One B-rep face of a CAD part: STEP entity #14088.
In plain terms, the planar face has unit normal (0, 0, -1).
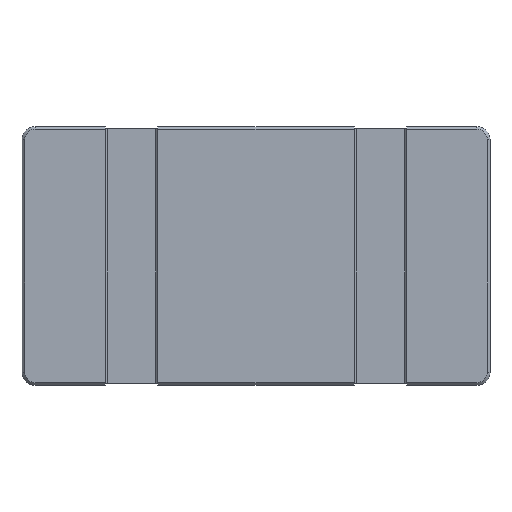
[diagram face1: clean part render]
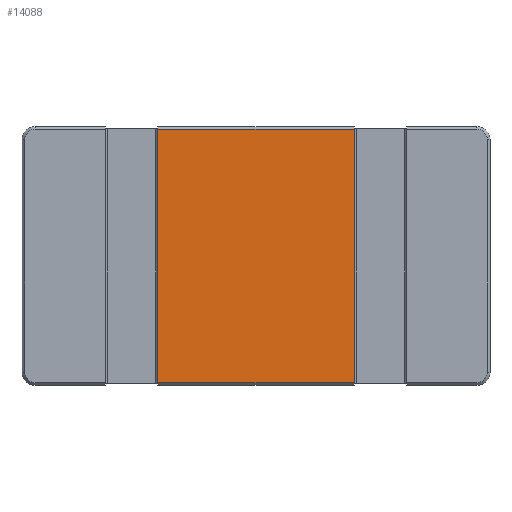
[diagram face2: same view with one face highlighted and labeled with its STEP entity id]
Its self-contained STEP definition (entity closure, numbers rounded to 3 decimals):
#10354 = PLANE('',#10355);
#10355 = AXIS2_PLACEMENT_3D('',#10356,#10357,#10358);
#10356 = CARTESIAN_POINT('',(-67.5,39.1,0.4));
#10357 = DIRECTION('',(0.,-0.707,0.707
    ));
#10358 = DIRECTION('',(-1.,0.,0.));
#11414 = PLANE('',#11415);
#11415 = AXIS2_PLACEMENT_3D('',#11416,#11417,#11418);
#11416 = CARTESIAN_POINT('',(67.5,-39.1,0.4));
#11417 = DIRECTION('',(0.,-0.707,
    -0.707));
#11418 = DIRECTION('',(-1.,0.,0.));
#12497 = PLANE('',#12498);
#12498 = AXIS2_PLACEMENT_3D('',#12499,#12500,#12501);
#12499 = CARTESIAN_POINT('',(-30.,-40.5,0.));
#12500 = DIRECTION('',(1.,0.,-0.));
#12501 = DIRECTION('',(0.,0.,1.));
#12560 = VERTEX_POINT('',#12561);
#12561 = CARTESIAN_POINT('',(30.,38.7,0.));
#12574 = PLANE('',#12575);
#12575 = AXIS2_PLACEMENT_3D('',#12576,#12577,#12578);
#12576 = CARTESIAN_POINT('',(30.,-40.5,0.));
#12577 = DIRECTION('',(1.,0.,-0.));
#12578 = DIRECTION('',(0.,0.,1.));
#12585 = EDGE_CURVE('',#12586,#12560,#12588,.T.);
#12586 = VERTEX_POINT('',#12587);
#12587 = CARTESIAN_POINT('',(-30.,38.7,0.));
#12588 = SURFACE_CURVE('',#12589,(#12593,#12600),.PCURVE_S1.);
#12589 = LINE('',#12590,#12591);
#12590 = CARTESIAN_POINT('',(-67.5,38.7,0.));
#12591 = VECTOR('',#12592,1.);
#12592 = DIRECTION('',(1.,0.,-0.));
#12593 = PCURVE('',#10354,#12594);
#12594 = DEFINITIONAL_REPRESENTATION('',(#12595),#12599);
#12595 = LINE('',#12596,#12597);
#12596 = CARTESIAN_POINT('',(-0.,0.566));
#12597 = VECTOR('',#12598,1.);
#12598 = DIRECTION('',(-1.,0.));
#12599 = ( GEOMETRIC_REPRESENTATION_CONTEXT(2) 
PARAMETRIC_REPRESENTATION_CONTEXT() REPRESENTATION_CONTEXT('2D SPACE',''
  ) );
#12600 = PCURVE('',#12601,#12606);
#12601 = PLANE('',#12602);
#12602 = AXIS2_PLACEMENT_3D('',#12603,#12604,#12605);
#12603 = CARTESIAN_POINT('',(-71.5,-39.5,0.));
#12604 = DIRECTION('',(0.,0.,1.));
#12605 = DIRECTION('',(1.,0.,-0.));
#12606 = DEFINITIONAL_REPRESENTATION('',(#12607),#12611);
#12607 = LINE('',#12608,#12609);
#12608 = CARTESIAN_POINT('',(4.,78.2));
#12609 = VECTOR('',#12610,1.);
#12610 = DIRECTION('',(1.,0.));
#12611 = ( GEOMETRIC_REPRESENTATION_CONTEXT(2) 
PARAMETRIC_REPRESENTATION_CONTEXT() REPRESENTATION_CONTEXT('2D SPACE',''
  ) );
#13096 = VERTEX_POINT('',#13097);
#13097 = CARTESIAN_POINT('',(-30.,-38.7,0.));
#13116 = EDGE_CURVE('',#13117,#13096,#13119,.T.);
#13117 = VERTEX_POINT('',#13118);
#13118 = CARTESIAN_POINT('',(30.,-38.7,0.));
#13119 = SURFACE_CURVE('',#13120,(#13124,#13131),.PCURVE_S1.);
#13120 = LINE('',#13121,#13122);
#13121 = CARTESIAN_POINT('',(67.5,-38.7,0.));
#13122 = VECTOR('',#13123,1.);
#13123 = DIRECTION('',(-1.,-0.,0.));
#13124 = PCURVE('',#11414,#13125);
#13125 = DEFINITIONAL_REPRESENTATION('',(#13126),#13130);
#13126 = LINE('',#13127,#13128);
#13127 = CARTESIAN_POINT('',(0.,0.566));
#13128 = VECTOR('',#13129,1.);
#13129 = DIRECTION('',(1.,0.));
#13130 = ( GEOMETRIC_REPRESENTATION_CONTEXT(2) 
PARAMETRIC_REPRESENTATION_CONTEXT() REPRESENTATION_CONTEXT('2D SPACE',''
  ) );
#13131 = PCURVE('',#12601,#13132);
#13132 = DEFINITIONAL_REPRESENTATION('',(#13133),#13137);
#13133 = LINE('',#13134,#13135);
#13134 = CARTESIAN_POINT('',(139.,0.8));
#13135 = VECTOR('',#13136,1.);
#13136 = DIRECTION('',(-1.,0.));
#13137 = ( GEOMETRIC_REPRESENTATION_CONTEXT(2) 
PARAMETRIC_REPRESENTATION_CONTEXT() REPRESENTATION_CONTEXT('2D SPACE',''
  ) );
#14067 = EDGE_CURVE('',#13096,#12586,#14068,.T.);
#14068 = SURFACE_CURVE('',#14069,(#14073,#14080),.PCURVE_S1.);
#14069 = LINE('',#14070,#14071);
#14070 = CARTESIAN_POINT('',(-30.,-40.5,0.));
#14071 = VECTOR('',#14072,1.);
#14072 = DIRECTION('',(-0.,1.,0.));
#14073 = PCURVE('',#12497,#14074);
#14074 = DEFINITIONAL_REPRESENTATION('',(#14075),#14079);
#14075 = LINE('',#14076,#14077);
#14076 = CARTESIAN_POINT('',(0.,0.));
#14077 = VECTOR('',#14078,1.);
#14078 = DIRECTION('',(0.,-1.));
#14079 = ( GEOMETRIC_REPRESENTATION_CONTEXT(2) 
PARAMETRIC_REPRESENTATION_CONTEXT() REPRESENTATION_CONTEXT('2D SPACE',''
  ) );
#14080 = PCURVE('',#12601,#14081);
#14081 = DEFINITIONAL_REPRESENTATION('',(#14082),#14086);
#14082 = LINE('',#14083,#14084);
#14083 = CARTESIAN_POINT('',(41.5,-1.));
#14084 = VECTOR('',#14085,1.);
#14085 = DIRECTION('',(0.,1.));
#14086 = ( GEOMETRIC_REPRESENTATION_CONTEXT(2) 
PARAMETRIC_REPRESENTATION_CONTEXT() REPRESENTATION_CONTEXT('2D SPACE',''
  ) );
#14088 = ADVANCED_FACE('',(#14089),#12601,.F.);
#14089 = FACE_BOUND('',#14090,.F.);
#14090 = EDGE_LOOP('',(#14091,#14092,#14093,#14114));
#14091 = ORIENTED_EDGE('',*,*,#14067,.F.);
#14092 = ORIENTED_EDGE('',*,*,#13116,.F.);
#14093 = ORIENTED_EDGE('',*,*,#14094,.T.);
#14094 = EDGE_CURVE('',#13117,#12560,#14095,.T.);
#14095 = SURFACE_CURVE('',#14096,(#14100,#14107),.PCURVE_S1.);
#14096 = LINE('',#14097,#14098);
#14097 = CARTESIAN_POINT('',(30.,-40.5,0.));
#14098 = VECTOR('',#14099,1.);
#14099 = DIRECTION('',(-0.,1.,0.));
#14100 = PCURVE('',#12601,#14101);
#14101 = DEFINITIONAL_REPRESENTATION('',(#14102),#14106);
#14102 = LINE('',#14103,#14104);
#14103 = CARTESIAN_POINT('',(101.5,-1.));
#14104 = VECTOR('',#14105,1.);
#14105 = DIRECTION('',(0.,1.));
#14106 = ( GEOMETRIC_REPRESENTATION_CONTEXT(2) 
PARAMETRIC_REPRESENTATION_CONTEXT() REPRESENTATION_CONTEXT('2D SPACE',''
  ) );
#14107 = PCURVE('',#12574,#14108);
#14108 = DEFINITIONAL_REPRESENTATION('',(#14109),#14113);
#14109 = LINE('',#14110,#14111);
#14110 = CARTESIAN_POINT('',(0.,0.));
#14111 = VECTOR('',#14112,1.);
#14112 = DIRECTION('',(0.,-1.));
#14113 = ( GEOMETRIC_REPRESENTATION_CONTEXT(2) 
PARAMETRIC_REPRESENTATION_CONTEXT() REPRESENTATION_CONTEXT('2D SPACE',''
  ) );
#14114 = ORIENTED_EDGE('',*,*,#12585,.F.);
